VERSION 5.7 ;
  NOWIREEXTENSIONATPIN ON ;
  DIVIDERCHAR "/" ;
  BUSBITCHARS "[]" ;
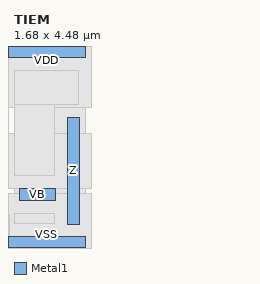
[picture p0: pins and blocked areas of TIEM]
MACRO TIEM
  CLASS core ;
  FOREIGN TIEM ;
  ORIGIN -1.680 0.000 ;
  SIZE 1.680 BY 4.480 ;
  SITE site056um ;
  PIN VSS
    DIRECTION INOUT ;
    USE GROUND ;
    PORT
      LAYER Metal1 ;
        RECT 0.000 -0.140 3.360 0.140 ;
    END
  END VSS
  PIN VDD
    DIRECTION INOUT ;
    USE POWER ;
    PORT
      LAYER Metal1 ;
        RECT 0.000 4.340 3.360 4.620 ;
    END
  END VDD
  PIN Z
    DIRECTION OUTPUT ;
    USE SIGNAL ;
    ANTENNAGATEAREA 0.246400 ;
    ANTENNADIFFAREA 0.303200 ;
    PORT
      LAYER Metal1 ;
        RECT 2.940 0.420 3.220 2.940 ;
    END
  END Z
  PIN VB
    DIRECTION INOUT ;
    USE POWER ;
    PORT
      LAYER Metal1 ;
        RECT 1.820 0.980 2.660 1.260 ;
    END
  END VB
  OBS
      LAYER Nwell ;
        RECT -0.085 3.160 3.695 4.755 ;
        RECT 1.680 2.560 3.360 3.160 ;
        RECT -0.085 1.260 3.695 2.560 ;
        RECT 1.680 1.135 3.360 1.260 ;
      LAYER Pwell ;
        RECT -0.085 -0.190 3.695 1.135 ;
      LAYER Metal1 ;
        RECT 0.695 1.780 0.925 4.340 ;
        RECT 1.680 3.240 3.195 4.040 ;
        RECT 1.680 1.560 2.640 3.240 ;
        RECT 0.445 0.885 1.150 1.115 ;
        RECT 0.445 0.370 0.675 0.885 ;
        RECT 1.230 0.140 1.570 0.655 ;
        RECT 1.680 0.440 2.640 0.680 ;
  END
END TIEM
END LIBRARY

